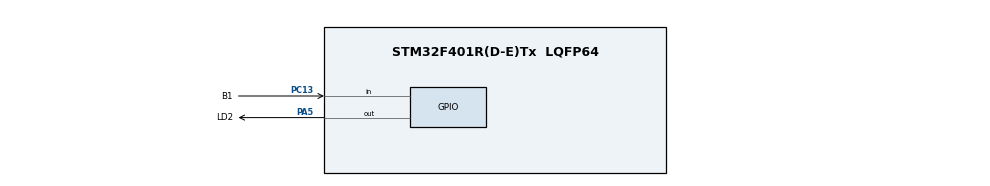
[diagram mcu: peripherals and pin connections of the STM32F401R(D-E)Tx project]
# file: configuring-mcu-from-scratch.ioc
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Mcu.Family=STM32F4
Mcu.Name=STM32F401R(D-E)Tx
Mcu.Package=LQFP64
NVIC.PriorityGroup=NVIC_PRIORITYGROUP_4
NVIC.TIM2_IRQn=true\:0\:0\:false\:false\:true\:true\:true\:true
PA5.GPIO_Label=LD2
PA5.Signal=GPIO_Output
PC13-ANTI_TAMP.GPIO_Label=B1
PC13-ANTI_TAMP.Signal=GPIO_Input
PC14-OSC32_IN.Mode=LSE-External-Oscillator
PC14-OSC32_IN.Signal=RCC_OSC32_IN
PC15-OSC32_OUT.Mode=LSE-External-Oscillator
PC15-OSC32_OUT.Signal=RCC_OSC32_OUT
PH0\ -\ OSC_IN.Mode=HSE-External-Clock-Source
PH0\ -\ OSC_IN.Signal=RCC_OSC_IN
PH1\ -\ OSC_OUT.Mode=HSE-External-Clock-Source
PH1\ -\ OSC_OUT.Signal=RCC_OSC_OUT
ProjectManager.HeapSize=0x200
ProjectManager.StackSize=0x400
ProjectManager.TargetToolchain=STM32CubeIDE
RCC.AHBFreq_Value=16000000
RCC.APB1Freq_Value=16000000
RCC.APB2Freq_Value=16000000
RCC.CortexFreq_Value=16000000
RCC.HSE_VALUE=25000000
RCC.HSI_VALUE=16000000
RCC.SYSCLKFreq_VALUE=16000000
RCC.VCOOutputFreq_Value=192000000
TIM2.Period=5001
TIM2.Prescaler=16000-1
VP_TIM2_VS_ClockSourceINT.Mode=Internal
board=custom

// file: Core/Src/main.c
/* USER CODE BEGIN Header */
/**
  ******************************************************************************
  * @file           : main.c
  * @brief          : Main program body
  ******************************************************************************
  * @attention
  *
  * Copyright (c) 2026 STMicroelectronics.
  * All rights reserved.
  *
  * This software is licensed under terms that can be found in the LICENSE file
  * in the root directory of this software component.
  * If no LICENSE file comes with this software, it is provided AS-IS.
  *
  ******************************************************************************
  */
/* USER CODE END Header */
#include "main.h"

TIM_HandleTypeDef htim2;

int8_t currentStatus= 0;
int8_t lastStatus= 0;

void SystemClock_Config(void);
static void MX_GPIO_Init(void);

static void MX_TIM2_Init(void);

int main(void)
{

  /* MCU Configuration--------------------------------------------------------*/

  /* Reset of all peripherals, Initializes the Flash interface and the Systick. */
  HAL_Init();

  /* Configure the system clock */
  SystemClock_Config();

  /* Initialize all configured peripherals */
  MX_GPIO_Init();
  MX_TIM2_Init();
  HAL_TIM_Base_Start_IT(&htim2);

  /* Infinite loop */
  while (1)
  {

  }
}

void SystemClock_Config(void)
{
  RCC_OscInitTypeDef RCC_OscInitStruct = {0};
  RCC_ClkInitTypeDef RCC_ClkInitStruct = {0};

  /** Configure the main internal regulator output voltage
  */
  __HAL_RCC_PWR_CLK_ENABLE();
  __HAL_PWR_VOLTAGESCALING_CONFIG(PWR_REGULATOR_VOLTAGE_SCALE2);

  /** Initializes the RCC Oscillators according to the specified parameters
  * in the RCC_OscInitTypeDef structure.
  */
  RCC_OscInitStruct.OscillatorType = RCC_OSCILLATORTYPE_HSI;
  RCC_OscInitStruct.HSIState = RCC_HSI_ON;
  RCC_OscInitStruct.HSICalibrationValue = RCC_HSICALIBRATION_DEFAULT;
  RCC_OscInitStruct.PLL.PLLState = RCC_PLL_ON;
  RCC_OscInitStruct.PLL.PLLSource = RCC_PLLSOURCE_HSI;
  RCC_OscInitStruct.PLL.PLLM = 16;
  RCC_OscInitStruct.PLL.PLLN = 336;
  RCC_OscInitStruct.PLL.PLLP = RCC_PLLP_DIV4;
  RCC_OscInitStruct.PLL.PLLQ = 7;
  if (HAL_RCC_OscConfig(&RCC_OscInitStruct) != HAL_OK)
  {
    Error_Handler();
  }

  /** Initializes the CPU, AHB and APB buses clocks
  */
  RCC_ClkInitStruct.ClockType = RCC_CLOCKTYPE_HCLK|RCC_CLOCKTYPE_SYSCLK
                              |RCC_CLOCKTYPE_PCLK1|RCC_CLOCKTYPE_PCLK2;
  RCC_ClkInitStruct.SYSCLKSource = RCC_SYSCLKSOURCE_PLLCLK;
  RCC_ClkInitStruct.AHBCLKDivider = RCC_SYSCLK_DIV1;
  RCC_ClkInitStruct.APB1CLKDivider = RCC_HCLK_DIV2;
  RCC_ClkInitStruct.APB2CLKDivider = RCC_HCLK_DIV1;

  if (HAL_RCC_ClockConfig(&RCC_ClkInitStruct, FLASH_LATENCY_2) != HAL_OK)
  {
    Error_Handler();
  }
}

static void MX_TIM2_Init(void)
{

  TIM_ClockConfigTypeDef sClockSourceConfig = {0};
  TIM_MasterConfigTypeDef sMasterConfig = {0};

  /*
   Prescaler = 16000 - 1 → PSC = 15999
	Period    = 500 - 1   → ARR = 499

	This goes for ~95ms for every interrupt action, since
	the system clock for the Nucleo-F401RE is 84MHz and
	following this equation:
	T= (PSC * ARR) / 84000000
	T= 0.095s
  */

  htim2.Instance = TIM2;
  htim2.Init.Prescaler = 16000-1;
  htim2.Init.CounterMode = TIM_COUNTERMODE_UP;
  htim2.Init.Period = 500-1;
  htim2.Init.ClockDivision = TIM_CLOCKDIVISION_DIV1;
  htim2.Init.AutoReloadPreload = TIM_AUTORELOAD_PRELOAD_DISABLE;
  if (HAL_TIM_Base_Init(&htim2) != HAL_OK)
  {
    Error_Handler();
  }
  sClockSourceConfig.ClockSource = TIM_CLOCKSOURCE_INTERNAL;
  if (HAL_TIM_ConfigClockSource(&htim2, &sClockSourceConfig) != HAL_OK)
  {
    Error_Handler();
  }
  sMasterConfig.MasterOutputTrigger = TIM_TRGO_RESET;
  sMasterConfig.MasterSlaveMode = TIM_MASTERSLAVEMODE_DISABLE;
  if (HAL_TIMEx_MasterConfigSynchronization(&htim2, &sMasterConfig) != HAL_OK)
  {
    Error_Handler();
  }

}

static void MX_GPIO_Init(void)
{
  GPIO_InitTypeDef GPIO_InitStruct = {0};

  /* GPIO Ports Clock Enable */
  __HAL_RCC_GPIOC_CLK_ENABLE();
  __HAL_RCC_GPIOH_CLK_ENABLE();
  __HAL_RCC_GPIOA_CLK_ENABLE();
  __HAL_RCC_GPIOB_CLK_ENABLE();

  /*Configure GPIO pin Output Level */
  HAL_GPIO_WritePin(LD2_GPIO_Port, LD2_Pin, GPIO_PIN_RESET);

  /*Configure GPIO pin : B1_Pin */
  GPIO_InitStruct.Pin = B1_Pin;
  GPIO_InitStruct.Mode = GPIO_MODE_IT_FALLING;
  GPIO_InitStruct.Pull = GPIO_NOPULL;
  HAL_GPIO_Init(B1_GPIO_Port, &GPIO_InitStruct);

  /*Configure GPIO pin : LD2_Pin */
  GPIO_InitStruct.Pin = LD2_Pin;
  GPIO_InitStruct.Mode = GPIO_MODE_OUTPUT_PP;
  GPIO_InitStruct.Pull = GPIO_NOPULL;
  GPIO_InitStruct.Speed = GPIO_SPEED_FREQ_LOW;
  HAL_GPIO_Init(LD2_GPIO_Port, &GPIO_InitStruct);

}

void Error_Handler(void)
{
  __disable_irq();
  while (1)
  {
  }
}

void HAL_TIM_PeriodElapsedCallback(TIM_HandleTypeDef *htim)
{
    if (htim->Instance == TIM2) // This happens every ~95ms
    {
    	// if lastStatus (last button state) was 0 and current status is 1 (pressed)...
    	if(lastStatus == 0 && HAL_GPIO_ReadPin(B1_GPIO_Port, B1_Pin) == GPIO_PIN_RESET){
    		// ...then change LED control state, so every B1 press either turns ON or OFF
    		// the LED blinking
    		if(currentStatus == 1){
    			currentStatus= 0;
    		}else{
    			currentStatus= 1;
    		}
    		lastStatus= 1;
    	// if lastStatus (last button state) was 1 and current is 0, means the button was
    	// released, re-start the logic
    	}else if(lastStatus == 1 && HAL_GPIO_ReadPin(B1_GPIO_Port, B1_Pin) == GPIO_PIN_SET){

    		lastStatus= 0;
    	}
    	// when currentStatus is 1 you can toggle the LED every ~95ms
    	if(currentStatus == 1){
    		HAL_GPIO_TogglePin(LD2_GPIO_Port, LD2_Pin);
    	}else{
    		// this is necessary so that if currentStatus goes to 0 and the LED
    		// is still ON (will happen frequently), turns the LED OFF.
    		HAL_GPIO_WritePin(LD2_GPIO_Port, LD2_Pin, GPIO_PIN_RESET);
    	}
    }
}
